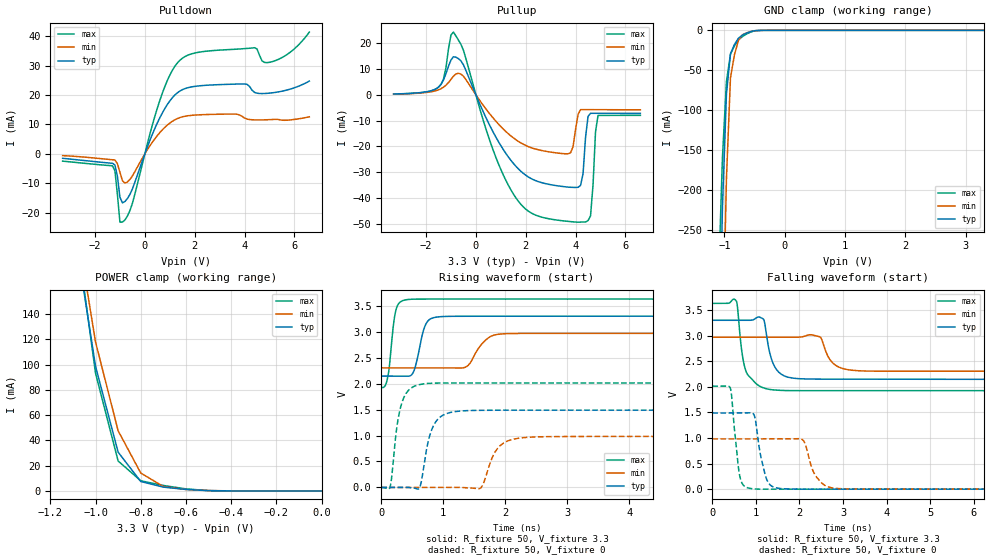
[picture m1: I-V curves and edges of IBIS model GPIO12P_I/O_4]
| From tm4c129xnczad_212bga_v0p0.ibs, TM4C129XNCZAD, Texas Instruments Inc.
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|   Model Cell GPIO12P_I/O_4
[Model]   GPIO12P_I/O_4
Model_type   I/O
Polarity   Non-Inverting
Enable   Active-Low
Vinl =  0.8
Vinh =  2
Cref =  15.0000pF
Rref =  100.0000M
Vref =  0V
Vmeas =  1.65
C_comp   6.029616p   5.226915p   6.778838p
[Model Spec]
Vinl   0.8   0.8   0.8
Vinh   2   2   2
[Temperature Range]   25   125   -40
[Voltage Range]   3.3   2.97   3.63
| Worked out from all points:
|   slope of the pulldown table from 0 to 0.495 V, typ, clamps not added: 47.6 ohm
|   slope of the pullup table from 0 to 0.495 V, typ, clamps not added: 46.2 ohm
|   GND clamp passes 1 mA (typ) near -0.53 V on its own axis
|   POWER clamp passes 1 mA (typ) near -0.58 V on its own axis
|   rising waveform, R_fixture 50, V_fixture 3.3: 20-80 % time 132ps typ, 227ps min, 91.1ps max; typ from 2.15 V to 3.3 V
|   rising waveform, R_fixture 50, V_fixture 0: 20-80 % time 170ps typ, 220ps min, 141ps max; typ from 0 V to 1.49 V
|   falling waveform, R_fixture 50, V_fixture 3.3: 20-80 % time 209ps typ, 256ps min, 187ps max; typ from 3.3 V to 2.15 V
|   falling waveform, R_fixture 50, V_fixture 0: 20-80 % time 190ps typ, 265ps min, 137ps max; typ from 1.49 V to 0 V
| Nom Voltages:
|   IBIASFET=3.3, VDDC=1.2, VDD=3.3, GND=0
| Min Voltages:
|   IBIASFET=2.97, VDDC=1.08, VDD=2.97, GND=0
| Max Voltages:
|   IBIASFET=3.63, VDDC=1.32, VDD=3.63, GND=0
[POWER_clamp]
|   voltage   I(typ)   I(min)   I(max)
-3.3V     3.668A     4.187A     4.057A
-1.067V   175.6mA    191.7mA    181.3mA
-1.033V   137.2mA    154.7mA    137.2mA
-1V       98.66mA    117.8mA    93.17mA
-900mV    30.66mA    47.6mA     23.68mA
-800mV    7.454mA    14.17mA    8.045mA
-700mV    3.021mA    3.466mA    4.326mA
-600mV    1.166mA    1.15mA     1.613mA
-500mV    219.7uA    295.1uA    245.5uA
0V        69.07pA    1.982nA    9.028pA
[Pulldown]
|   voltage   I(typ)   I(min)   I(max)
-3.3V     -1.509mA   -602.7uA   -2.468mA
-1.3V     -3.207mA   -2.003mA   -4.042mA
-1.2V     -3.806mA   -2.081mA   -5.788mA
-1V       -14.75mA   -6.263mA   -23.22mA
-900mV    -16.65mA   -9.096mA   -23.18mA
-500mV    -11.93mA   -7.502mA   -16.82mA
700mV     13.88mA    8.154mA    20.58mA
1.4V      21.31mA    12.31mA    31.75mA
4V        23.75mA    12.18mA    35.77mA
4.4V      20.89mA    11.55mA    36.08mA
5V        20.64mA    11.62mA    31.11mA
6.6V      24.74mA    12.6mA     41.38mA
[Pullup]
|   voltage   I(typ)   I(min)   I(max)
-3.3V     313uA      267.8uA    282.6uA
-1.5V     2.981mA    1.923mA    2.934mA
-900mV    14.77mA    7.231mA    24.34mA
1.5V      -26.59mA   -16.71mA   -38.47mA
3.9V      -35.95mA   -20.15mA   -49.34mA
4.2V      -35.21mA   -5.776mA   -49.44mA
4.3V      -30.65mA   -5.775mA   -49.41mA
4.5V      -8.41mA    -5.777mA   -48.85mA
4.6V      -7.197mA   -5.778mA   -47.04mA
4.8V      -7.189mA   -5.783mA   -14.42mA
4.9V      -7.187mA   -5.785mA   -8.03mA
6.6V      -7.206mA   -5.847mA   -7.984mA
[GND_clamp]
|   voltage   I(typ)   I(min)   I(max)
-3.3V     -18.01A    -17.27A    -18.6A
-1.1V     -459.9mA   -734.3mA   -318.7mA
-1.033V   -223.6mA   -411.6mA   -160.4mA
-966.7mV  -80.12mA   -186.8mA   -64.21mA
-900mV    -29.51mA   -59.8mA    -30.11mA
-833.3mV  -17.66mA   -30.4mA    -19.41mA
-766.7mV  -9.785mA   -12.28mA   -11.96mA
-700mV    -5.884mA   -5.445mA   -7.749mA
-500mV    -484.3uA   -573uA     -552.3uA
-366.7mV  -23.48uA   -48.41uA   -21.82uA
3.3V      69.07pA    6.412uA    7.794pA
[Ramp]
| variable   typ   min   max
dV/dt_f 0.73233416/0.208251n  0.42778703/0.25767386n  1.0739608/0.18300474n
dV/dt_r 0.91398213/0.17088204n  0.6067156/0.22172054n  1.2266885/0.14186562n
R_load = 50
[Rising Waveform]
R_fixture = 50
V_fixture = 3.3
V_fixture_min = 2.97
V_fixture_max = 3.63
|   time   V(typ)   V(min)   V(max)
0s        2.146V     2.304V     1.925V
108.7ps   2.146V     2.304V     2.157V
238.1ps   2.146V     2.304V     3.432V
446ps     2.145V     2.304V     3.624V
722.3ps   3.156V     2.304V     3.63V
1.005ns   3.294V     2.304V     3.63V
1.378ns   3.299V     2.33V      3.63V
1.715ns   3.299V     2.872V     3.63V
2.034ns   3.3V       2.964V     3.63V
20.03ns   3.3V       2.97V      3.63V
[Rising Waveform]
R_fixture = 50
V_fixture = 0
V_fixture_min = 0
V_fixture_max = 0
|   time   V(typ)   V(min)   V(max)
0s        0V         0V         0V
149ps     0V         0V         44.08mV
364.2ps   0V         0V         1.735V
611.9ps   -17.96mV   0V         1.981V
738ps     783.3mV    0V         2.003V
984.6ps   1.386V     0V         2.012V
1.584ns   1.486V     -24.42mV   2.013V
1.911ns   1.488V     798mV      2.013V
2.434ns   1.489V     970.2mV    2.013V
20.01ns   1.489V     982.4mV    2.013V
[Falling Waveform]
R_fixture = 50
V_fixture = 3.3
V_fixture_min = 2.97
V_fixture_max = 3.63
|   time   V(typ)   V(min)   V(max)
0s        3.3V       2.97V      3.63V
551.5ps   3.3V       2.97V      3.674V
669.3ps   3.3V       2.97V      2.734V
751ps     3.3V       2.97V      2.358V
1.164ns   3.328V     2.97V      1.982V
1.409ns   2.43V      2.97V      1.939V
2.472ns   2.15V      2.975V     1.925V
2.8ns     2.149V     2.439V     1.925V
3.348ns   2.149V     2.314V     1.925V
20.03ns   2.146V     2.304V     1.925V
[Falling Waveform]
R_fixture = 50
V_fixture = 0
V_fixture_min = 0
V_fixture_max = 0
|   time   V(typ)   V(min)   V(max)
0s        1.489V     981.9mV    2.013V
410.8ps   1.489V     981.9mV    1.978V
625.6ps   1.489V     981.9mV    268mV
922.4ps   1.485V     981.9mV    7.58mV
1.248ns   187.7mV    981.9mV    0V
1.607ns   9.54mV     981.8mV    0V
2.065ns   0V         970.6mV    0V
2.388ns   0V         241.2mV    0V
2.88ns    0V         12.53mV    0V
20.01ns   0V         0V         0V
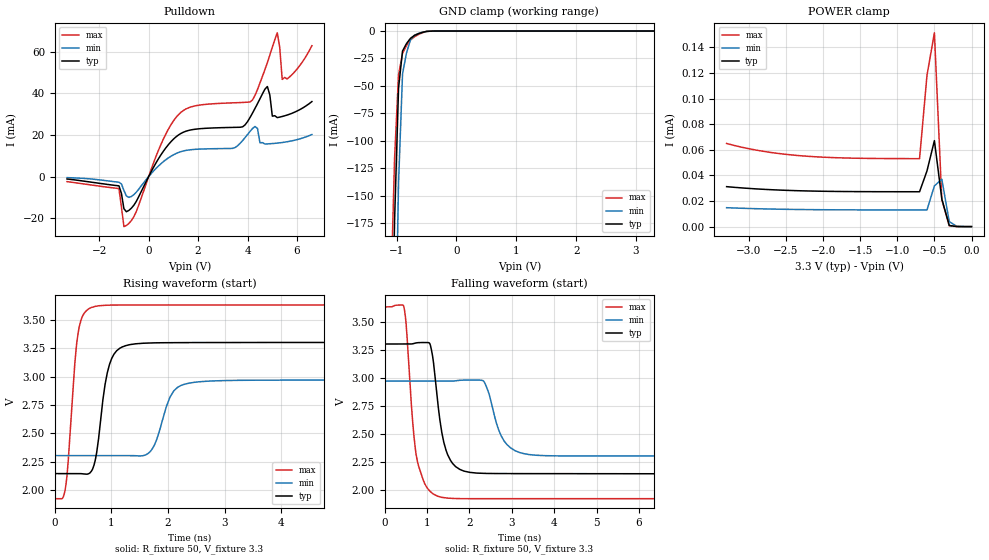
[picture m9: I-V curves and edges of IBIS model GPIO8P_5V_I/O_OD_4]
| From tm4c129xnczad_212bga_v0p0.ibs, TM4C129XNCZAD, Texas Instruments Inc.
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|   Model Cell GPIO8P_5V_I/O_OD_4
[Model]   GPIO8P_5V_I/O_OD_4
Model_type   I/O_open_drain
Polarity   Inverting
Enable   Active-Low
Vinl =  0.8
Vinh =  2
Cref =  15.0000pF
Rref =  100.0000M
Vref =  0V
Vmeas =  1.65
C_comp   7.738177p   6.063161p   9.392973p
[Model Spec]
Vinl   0.8   0.8   0.8
Vinh   2   2   2
[Temperature Range]   25   125   -40
[Voltage Range]   3.3   2.97   3.63
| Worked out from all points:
|   slope of the pulldown table from 0 to 0.495 V, typ, clamps not added: 47.6 ohm
|   GND clamp passes 1 mA (typ) near -0.55 V on its own axis
|   rising waveform, R_fixture 50, V_fixture 3.3: 20-80 % time 194ps typ, 262ps min, 148ps max; typ from 2.15 V to 3.3 V
|   falling waveform, R_fixture 50, V_fixture 3.3: 20-80 % time 259ps typ, 342ps min, 226ps max; typ from 3.3 V to 2.15 V
| Nom Voltages:
|   VDDC=1.2, VDD=3.3, GND=0
| Min Voltages:
|   VDDC=1.08, VDD=2.97, GND=0
| Max Voltages:
|   VDDC=1.32, VDD=3.63, GND=0
[POWER_clamp]
|   voltage   I(typ)   I(min)   I(max)
-3.3V     31.22uA    14.77uA    64.95uA
-2.8V     29.13uA    13.84uA    58.77uA
-2.3V     27.98uA    13.34uA    55.36uA
-1.7V     27.4uA     13.1uA     53.62uA
-700mV    27.24uA    13.03uA    53.12uA
-600mV    43.52uA    13.03uA    118.2uA
-500mV    67.2uA     31.8uA     151.5uA
-400mV    21.58uA    37.04uA    21.1uA
-300mV    927.4nA    3.873uA    611.4nA
-200mV    28.93nA    266.5nA    11.51nA
0V        696.9pA    10.99nA    568.3pA
[Pulldown]
|   voltage   I(typ)   I(min)   I(max)
-3.3V     -1.162mA   -505.3uA   -2.413mA
-1.2V     -4.448mA   -2.72mA    -5.833mA
-1V       -15.42mA   -6.655mA   -24.03mA
-900mV    -16.9mA    -9.327mA   -23.48mA
1.2V      19.95mA    11.56mA    29.71mA
3.4V      23.64mA    13.58mA    35.45mA
4.1V      28.41mA    21.71mA    35.87mA
4.8V      43.29mA    15.72mA    54.81mA
5V        29.04mA    15.88mA    62.21mA
5.2V      28.35mA    16.1mA     69.11mA
5.4V      28.9mA     16.38mA    46.73mA
6.6V      36.05mA    20.22mA    62.9mA
[GND_clamp]
|   voltage   I(typ)   I(min)   I(max)
-3.3V     -16.36A    -15.34A    -17.18A
-1.1V     -382.1mA   -633.4mA   -250.1mA
-1.033V   -173.3mA   -336.5mA   -116.4mA
-966.7mV  -52.02mA   -138.4mA   -39.81mA
-900mV    -18.21mA   -38.98mA   -20.34mA
-833.3mV  -11.36mA   -19.82mA   -13.17mA
-766.7mV  -6.618mA   -8.051mA   -8.134mA
-700mV    -3.983mA   -3.675mA   -5.247mA
-500mV    -328.3uA   -388.2uA   -374.5uA
-366.7mV  -15.94uA   -32.84uA   -14.83uA
3.3V      697pA      8.348uA    426.1pA
[Ramp]
| variable   typ   min   max
dV/dt_f 0.70109912/0.26037919n 0.40520664/0.34382932n  1.0338228/0.22628195n
dV/dt_r 0.90140807/0.45275695n 0.59660584/0.74446515n  1.2150245/0.33158972n
R_load = 50
[Rising Waveform]
R_fixture = 50
V_fixture = 3.3
V_fixture_min = 2.97
V_fixture_max = 3.63
|   time   V(typ)   V(min)   V(max)
0s        2.146V     2.304V     1.925V
199.6ps   2.146V     2.304V     2.057V
430.8ps   2.146V     2.304V     3.435V
774.7ps   2.456V     2.304V     3.622V
1.006ns   3.159V     2.304V     3.628V
1.421ns   3.288V     2.303V     3.629V
1.717ns   3.296V     2.359V     3.63V
2.103ns   3.298V     2.874V     3.63V
2.648ns   3.299V     2.957V     3.63V
20.14ns   3.3V       2.97V      3.63V
[Falling Waveform]
R_fixture = 50
V_fixture = 3.3
V_fixture_min = 2.97
V_fixture_max = 3.63
|   time   V(typ)   V(min)   V(max)
0s        3.3V       2.97V      3.63V
457.4ps   3.3V       2.97V      3.628V
743.2ps   3.31V      2.97V      2.318V
1.058ns   3.308V     2.97V      1.996V
1.348ns   2.519V     2.97V      1.937V
1.677ns   2.209V     2.973V     1.926V
2.336ns   2.15V      2.97V      1.925V
2.818ns   2.148V     2.439V     1.925V
3.572ns   2.147V     2.311V     1.925V
20.14ns   2.146V     2.304V     1.925V
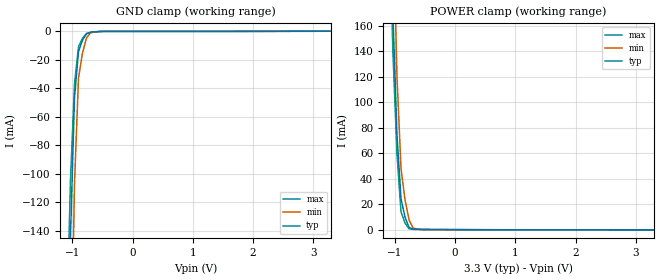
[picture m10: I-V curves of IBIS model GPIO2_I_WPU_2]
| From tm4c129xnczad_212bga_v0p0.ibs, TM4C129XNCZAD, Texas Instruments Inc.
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|   Model Cell GPIO2_I_WPU_2
[Model]   GPIO2_I_WPU_2
Model_type   Input
Polarity   Non-Inverting
Vinl =  0.8
Vinh =  2
C_comp   3.906872p   3.211855p   4.659324p
[Model Spec]
Vinl   0.8   0.8   0.8
Vinh   2   2   2
[Temperature Range]   25   125   -40
[Voltage Range]   3.3   2.97   3.63
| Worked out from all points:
|   GND clamp passes 1 mA (typ) near -0.72 V on its own axis
|   POWER clamp passes 1 mA (typ) near -0.73 V on its own axis
| Nom Voltages:
|   IBIASFET=3.3, VDDC=1.2, VDDA=3.3, VDD=3.3, GND=0, GNDA=0
| Min Voltages:
|   IBIASFET=2.97, VDDC=1.08, VDDA=2.97, VDD=2.97, GND=0, GNDA=0
| Max Voltages:
|   IBIASFET=3.63, VDDC=1.32, VDDA=3.63, VDD=3.63, GND=0, GNDA=0
[POWER_clamp]
|   voltage   I(typ)   I(min)   I(max)
-3.3V     12.79A     11.69A     13.85A
-1.1V     303.6mA    434.7mA    250.1mA
-1.033V   167.3mA    248.8mA    138.3mA
-966.7mV  74.21mA    120mA      59.52mA
-900mV    24.31mA    48.18mA    13.92mA
-833.3mV  9.861mA    23.35mA    5.209mA
-766.7mV  1.86mA     7.726mA    669.8uA
-700mV    304.9uA    1.303mA    306.8uA
-566.7mV  113.6uA    148.8uA    145.9uA
3.3V      -165.6uA   -95.6uA    -263uA
[GND_clamp]
|   voltage   I(typ)   I(min)   I(max)
-3.3V     -13.29A    -11.96A    -14.49A
-1.1V     -306.4mA   -502mA     -214mA
-1.033V   -144.1mA   -263.6mA   -104.9mA
-966.7mV  -46.75mA   -107.2mA   -37.23mA
-900mV    -14.24mA   -32.82mA   -11.07mA
-833.3mV  -6.336mA   -15.28mA   -4.999mA
-766.7mV  -1.838mA   -4.72mA    -1.625mA
-700mV    -749.7uA   -1.155mA   -952.7uA
-500mV    -189.3uA   -137.2uA   -281.4uA
3.3V      266.5fA    32.56uA    -61.41uA
